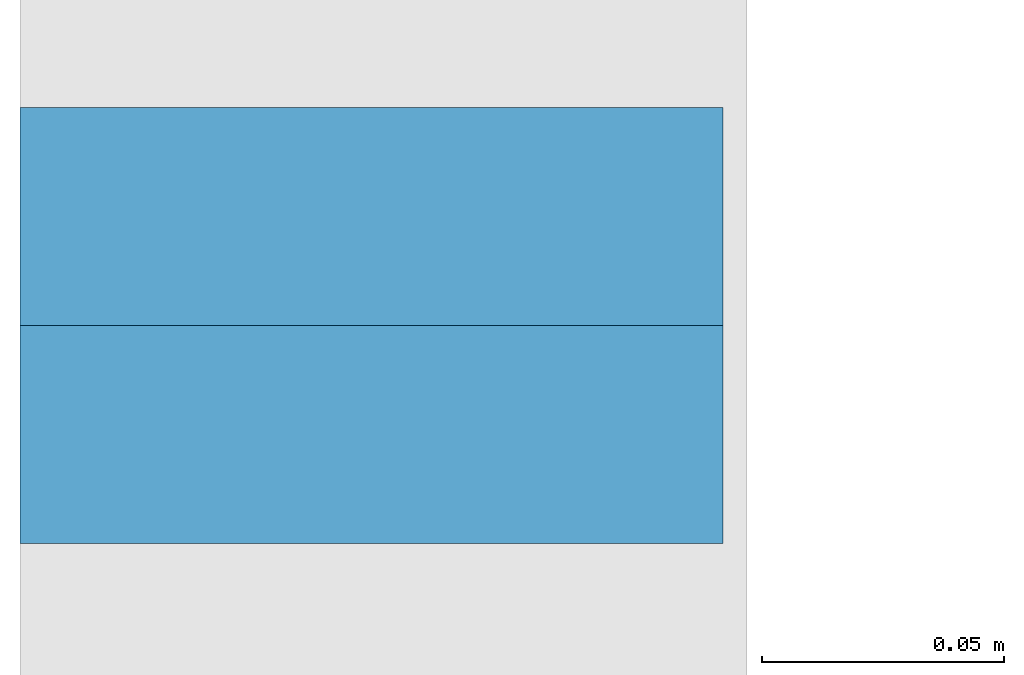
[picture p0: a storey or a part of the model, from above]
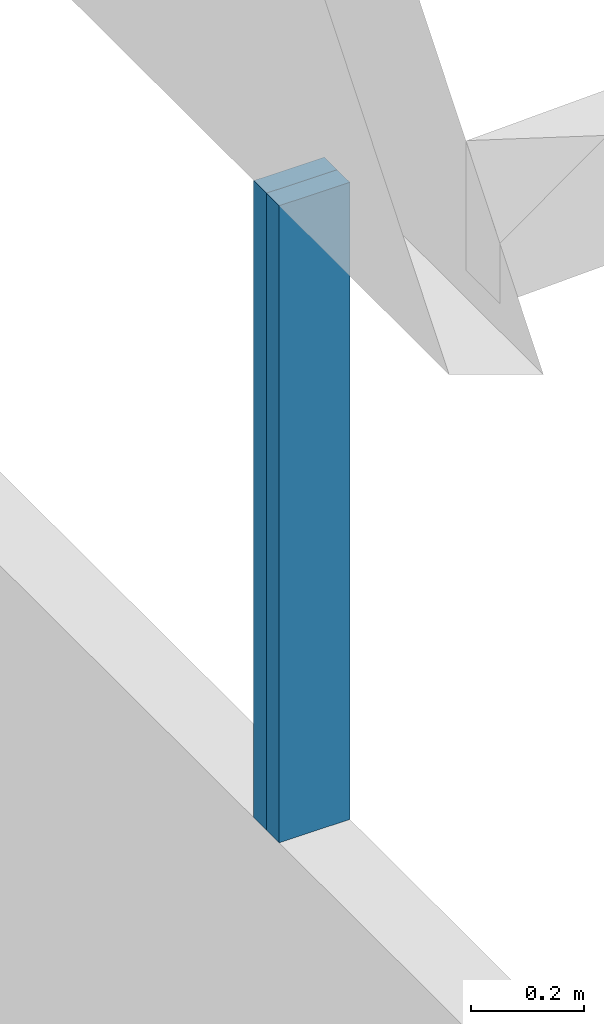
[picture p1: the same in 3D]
Properties of the parts of a building model (IFC2X3)

# File
Description: ViewDefinition[CoordinationView_V1.0], Option [GridExport:On], Option [Include assembly hierarchy:On], Option [Bolts:On], Option [Rebars:On], Option [PourObjects:Off], Option [Welds:Off], Option [SurfaceTreatments:On], Option [LocationBy:0], Option [ViewColors:On], Option [SectionedSpine:Off], Option [PropertySets:On], Option [Export all:Off], Option [Export selected and their assemblies:Off]
File name: IFC.ifc
Time: 2026-06-24T15:56:22
Author: INTECH\Bastien
Organization: Structural Designer
Written by: IFC Parser Version: 4.12.3
Made in: Trimble Inc. - Tekla Structures - 2026.0.60984.0

# IfcBuildingStorey, Undefined
In: Undefined
Elevation: 0 mm

# IfcBeam: 100*140 (2)
In: Undefined
Description: 100*140; Material: TIMBER/C24
Tekla Commun - Nom: BUTON; Profil: 100*140; Matériau: C24; Classe: 203; Phase: 1; Repère: Bu-b0(?); Repère assemblage: Bu-b0(?)
Tekla Quantités - Longueur: 1520 mm; Largeur: 140 mm; Hauteur: 100 mm; Surface nette: 0.758 m2; Surface par tonne: 84.765 m2; Surface: 0 m2; Volume: 0.021 m3; Poids: 8.94 kg
BeamBaseQuantities - Longueur: 1520 mm; Surface extérieure: 0.7 m2; Volume net: 0 m3; Poids net: 8.8 kg
Pset_BeamCommon - Inclinaison: 0 rad
Name | Niveau haut | Niveau bas
BUTON | +3.063 | +2.920
BUTON | +2.990 | +2.847

# IfcBeam: 120*280 (8)
In: Undefined
Description: 120*280; Material: TIMBER/C24
Tekla Commun - Profil: 120*280; Matériau: C24; Phase: 1
Tekla Quantités - Largeur: 280 mm; Hauteur: 120 mm; Surface: 0 m2
Name | Nom | Classe | Repère = Repère assemblage | Niveau haut | Niveau bas | Tekla Quantités, Longueur (mm) = BeamBaseQuantities, Longueur (mm) | Surface nette (m2) | Surface par tonne (m2) | Volume (m3) | Poids (kg) | Surface extérieure (m2) | Volume net (m3) | Poids net (kg) | Inclinaison (rad)
LIGNEUL | LIGNEUL | 207 | LL-b0(?) | +3.118 | +2.726 | 3834.5 | 3.135 | 57.931 | 0.129 | 54.11 | 3.1 | 0.1 | 54.1 | 0.02931
CHEVRONS | CHEVRONS | 201 | Cvr-b0(?) | +3.005 | +2.650 | 2171.1 | 1.796 | 58.894 | 0.073 | 30.5 | 1.8 | 0.1 | 30.5 | 0.03491
CHEVRONS | CHEVRONS | 201 | Cvr-b0(?) | +3.104 | +2.650 | 4996.8 | 4.011 | 58.072 | 0.164 | 69.07 | 4 | 0.2 | 69.1 | 0.03491
CHEVRONS | CHEVRONS | 201 | Cvr-b0(?) | +3.118 | +2.650 | 5386.4 | 4.368 | 57.576 | 0.181 | 75.87 | 4.4 | 0.2 | 75.9 | 0.03491
CHEVRONS | CHEVRONS | 201 | Cvr-b0(?) | +3.117 | +2.650 | 5381.3 | 4.364 | 57.576 | 0.18 | 75.8 | 4.4 | 0.2 | 75.8 | 0.03491
CHEVRONS | CHEVRONS | 201 | Cvr-b0(?) | +3.117 | +2.650 | 5376.2 | 4.36 | 57.576 | 0.18 | 75.73 | 4.4 | 0.2 | 75.8 | 0.03491
2 x CHEVRONS | CHEVRONS | 201 | Cvr-b0(?) | +3.120 | +2.650 | 5453.1 | 4.422 | 57.565 | 0.183 | 76.82 | 4.4 | 0.2 | 76.8 | 0.03491

# IfcBeam: 150*210 (5)
In: Undefined
Description: 150*210; Material: CONCRETE/C25/30
Tekla Commun - Nom: POUTRE; Profil: 150*210; Matériau: C25/30; Classe: 1; Phase: 1; Repère: Po0(?); Repère assemblage: Po0(?); Niveau haut: +0.210; Niveau bas: -0.000
Tekla Quantités - Largeur: 210 mm; Hauteur: 150 mm
Pset_BeamCommon - Inclinaison: 0 rad
Name | Tekla Quantités, Longueur (mm) = BeamBaseQuantities, Longueur (mm) | Surface nette (m2) | Surface par tonne (m2) | Surface (m2) | Volume (m3) | Poids (kg) | Surface extérieure (m2) | Volume net (m3) | Poids net (kg)
POUTRE | 435 | 0.376 | 11.44 | 0.065 | 0.014 | 32.89 | 0.4 | 0 | 32.9
POUTRE | 415 | 0.362 | 11.532 | 0.062 | 0.014 | 31.37 | 0.4 | 0 | 31.4
POUTRE | 5730 | 4.189 | 9.669 | 0.86 | 0.18 | 433.19 | 4.2 | 0.2 | 433.2
POUTRE | 10530 | 7.645 | 9.603 | 1.58 | 0.332 | 796.07 | 7.7 | 0.3 | 796.1
POUTRE | 2305 | 1.723 | 9.885 | 0.346 | 0.073 | 174.26 | 1.8 | 0.1 | 174.3

# IfcBeam: 170*1030, POUTRE
In: Undefined
Description: 170*1030; Material: CONCRETE/C25/30
Tekla Commun - Nom: POUTRE; Profil: 170*1030; Matériau: C25/30; Classe: 2; Phase: 1; Repère: Po0(?); Repère assemblage: Po0(?); Niveau haut: +3.630; Niveau bas: +2.600
Tekla Quantités - Longueur: 3490.7 mm; Largeur: 1030 mm; Hauteur: 170 mm; Surface nette: 8.728 m2; Surface par tonne: 5.95 m2; Surface: 0.593 m2; Volume: 0.611 m3; Poids: 1466.91 kg
BeamBaseQuantities - Longueur: 3490.7 mm; Surface extérieure: 8.7 m2; Volume net: 0.6 m3; Poids net: 1466.9 kg
Pset_BeamCommon - Inclinaison: 0 rad

# IfcBeam: 50*100 (12)
In: Undefined
Description: 50*100; Material: TIMBER/C24
Tekla Commun - Nom: CHEVETRE; Profil: 50*100; Matériau: C24; Classe: 204; Phase: 1; Repère: Ch-b0(?); Repère assemblage: Ch-b0(?)
Tekla Quantités - Largeur: 100 mm; Hauteur: 50 mm; Surface: 0 m2
BeamBaseQuantities - Volume net: 0 m3
Name | Niveau haut | Niveau bas | Tekla Quantités, Longueur (mm) = BeamBaseQuantities, Longueur (mm) | Surface nette (m2) | Surface par tonne (m2) | Volume (m3) | Poids (kg) | Surface extérieure (m2) | Poids net (kg) | Inclinaison (rad)
4 x CHEVETRE | +2.954 | +2.846 | 250 | 0.085 | 161.905 | 0.001 | 0.53 | 0.1 | 0.5 | 0.03491
CHEVETRE | +2.946 | +2.844 | 1520 | 0.466 | 145.99 | 0.008 | 3.19 | 0.4 | 3.2 | 0
CHEVETRE | +2.956 | +2.855 | 1520 | 0.466 | 145.99 | 0.008 | 3.19 | 0.4 | 3.2 | 0
CHEVETRE | +2.946 | +2.844 | 1580 | 0.484 | 145.871 | 0.008 | 3.32 | 0.4 | 3.3 | 0
CHEVETRE | +2.956 | +2.855 | 1580 | 0.484 | 145.871 | 0.008 | 3.32 | 0.4 | 3.3 | 0
CHEVETRE | +3.011 | +2.909 | 400 | 0.13 | 154.762 | 0.002 | 0.84 | 0.1 | 0.9 | 0
CHEVETRE | +2.995 | +2.894 | 400 | 0.13 | 154.762 | 0.002 | 0.84 | 0.1 | 0.9 | 0
2 x CHEVETRE | +3.060 | +2.890 | 2000 | 0.61 | 145.238 | 0.009 | 4.2 | 0.7 | 4.2 | 0.03491

# IfcBeam: 70*140 (17)
In: Undefined
Description: 70*140; Material: TIMBER/C24
Tekla Commun - Nom: BUTON; Profil: 70*140; Matériau: C24; Phase: 1; Repère: Bu-b0(?); Repère assemblage: Bu-b0(?)
Tekla Quantités - Largeur: 140 mm; Hauteur: 70 mm; Surface: 0 m2
BeamBaseQuantities - Volume net: 0 m3
Name | Classe | Niveau haut | Niveau bas | Tekla Quantités, Longueur (mm) = BeamBaseQuantities, Longueur (mm) | Surface nette (m2) | Surface par tonne (m2) | Volume (m3) | Poids (kg) | Surface extérieure (m2) | Poids net (kg) | Inclinaison (rad)
BUTON | 202 | +2.849 | +2.649 | 2370 | 1.015 | 104.05 | 0.023 | 9.75 | 0.9 | 9.8 | 0.02462
4 x BUTON | 202 | +2.849 | +2.649 | 2384.2 | 1.021 | 104.038 | 0.023 | 9.81 | 0.9 | 9.8 | 0.02447
BUTON | 202 | +2.849 | +2.649 | 2341.8 | 1.003 | 104.074 | 0.023 | 9.64 | 0.9 | 9.6 | 0.02492
BUTON | 202 | +2.923 | +2.708 | 2701.9 | 1.154 | 103.803 | 0.026 | 11.12 | 1.2 | 11.1 | 0.02713
BUTON | 202 | +2.978 | +2.781 | 2330.8 | 0.999 | 104.084 | 0.023 | 9.59 | 0.9 | 9.6 | 0.02388
4 x BUTON | 203 | +3.063 | +2.921 | 1580 | 0.683 | 105.055 | 0.014 | 6.5 | 0.7 | 6.5 | 0
BUTON | 203 | +2.990 | +2.847 | 1560 | 0.675 | 105.093 | 0.014 | 6.42 | 0.7 | 6.5 | 0
4 x BUTON | 203 | +2.990 | +2.847 | 1580 | 0.683 | 105.055 | 0.014 | 6.5 | 0.7 | 6.5 | 0

# IfcBeam: C40*30*2 (4)
In: Undefined
Description: C40*30*2; Material: STEEL/S235JR
Tekla Commun - Nom: OMEGA; Profil: C40*30*2; Matériau: S235JR; Classe: 503; Phase: 1; Repère: Om0(?); Repère assemblage: Om0(?); Niveau haut: +2.970; Niveau bas: +2.940
Tekla Quantités - Largeur: 30 mm; Hauteur: 40 mm
BeamBaseQuantities - Volume net: 0 m3
Pset_BeamCommon - Inclinaison: 0 rad
Name | Tekla Quantités, Longueur (mm) = BeamBaseQuantities, Longueur (mm) | Surface nette (m2) | Surface par tonne (m2) | Surface (m2) | Volume (m3) | Poids (kg) | Surface extérieure (m2) | Poids net (kg)
OMEGA | 1900 | 0.373 | 130.177 | 0.076 | 0 | 2.86 | 0.4 | 2.9
3 x OMEGA | 3480 | 0.682 | 130.116 | 0.139 | 0.001 | 5.25 | 0.7 | 5.2

# IfcBeam: D20 (4)
In: Undefined
Description: D20; Material: STEEL/S235JR
Tekla Commun - Nom: TIRANT; Profil: D20; Matériau: S235JR; Classe: 202; Phase: 1; Repère: Cv0(?); Repère assemblage: Cv0(?); Niveau haut: +3.100; Niveau bas: +2.897
Tekla Quantités - Longueur: 3507.4 mm; Largeur: 20 mm; Hauteur: 20 mm; Surface nette: 0.215 m2; Surface par tonne: 27.65 m2; Surface: 0 m2; Volume: 0.001 m3; Poids: 7.79 kg
BeamBaseQuantities - Longueur: 3507.4 mm; Surface extérieure: 0.2 m2; Volume net: 0 m3; Poids net: 7.8 kg
Pset_BeamCommon - Inclinaison: 0.05216 rad

# IfcBeam: TUBE-C-100*100*3 (10)
In: Undefined
Description: TUBE-C-100*100*3; Material: STEEL/S235JR
Tekla Commun - Nom: TUBE; Profil: TUBE-C-100*100*3; Matériau: S235JR; Classe: 203; Phase: 1; Repère: Tu0(?); Repère assemblage: Tu0(?)
Tekla Quantités - Largeur: 100 mm; Hauteur: 100 mm; Surface par tonne: 43.58 m2
BeamBaseQuantities - Surface extérieure: 0.4 m2; Volume net: 0 m3
Pset_BeamCommon - Inclinaison: 0 rad
Name | Niveau haut | Niveau bas | Tekla Quantités, Longueur (mm) = BeamBaseQuantities, Longueur (mm) | Surface nette (m2) | Surface (m2) | Volume (m3) | Poids (kg) | Poids net (kg)
2 x TUBE | +0.250 | +0.150 | 1320 | 0.529 | 0.132 | 0.002 | 11.81 | 12.1
2 x TUBE | +1.720 | +1.620 | 1320 | 0.529 | 0.132 | 0.002 | 11.81 | 12.1
3 x TUBE | +0.250 | +0.150 | 920 | 0.369 | 0.092 | 0.001 | 8.23 | 8.4
3 x TUBE | +1.720 | +1.620 | 920 | 0.369 | 0.092 | 0.001 | 8.23 | 8.4

# IfcBeam: TUBE-C-80*80*3 (87)
In: Undefined
Description: TUBE-C-80*80*3; Material: STEEL/S235JR
Tekla Commun - Profil: TUBE-C-80*80*3; Matériau: S235JR; Phase: 1
Tekla Quantités - Largeur: 80 mm; Hauteur: 80 mm; Surface par tonne: 43.688 m2
BeamBaseQuantities - Volume net: 0 m3
Name | Nom | Classe | Repère = Repère assemblage | Niveau haut | Niveau bas | Tekla Quantités, Longueur (mm) = BeamBaseQuantities, Longueur (mm) | Surface nette (m2) | Surface (m2) | Volume (m3) | Poids (kg) | Surface extérieure (m2) | Poids net (kg) | Inclinaison (rad)
LISSE | LISSE | 207 | L0(?) | +3.630 | +3.550 | 1595.6 | 0.512 | 0.128 | 0.001 | 11.29 | 0.4 | 11.6 | 0
LISSE | LISSE | 207 | L0(?) | +3.050 | +2.970 | 1595.6 | 0.512 | 0.128 | 0.001 | 11.29 | 0.4 | 11.6 | 0
TREILLIS | TREILLIS | 200 | Tr0(?) | +3.010 | +2.880 | 129.8 | 0.043 | 0.001 | 0 | 0.92 | 0 | 0.9 | 1.5708
2 x TREILLIS | TREILLIS | 200 | Tr0(?) | +2.400 | +2.320 | 1115 | 0.358 | 0.089 | 0.001 | 7.89 | 0.4 | 8.1 | 0
TREILLIS | TREILLIS | 200 | Tr0(?) | +2.880 | +2.800 | 1750 | 0.561 | 0.14 | 0.002 | 12.38 | 0.4 | 12.7 | 0
LISSE | LISSE | 207 | L0(?) | +3.050 | +2.970 | 1900 | 0.609 | 0.152 | 0.002 | 13.44 | 0.7 | 13.8 | 0
LISSE | LISSE | 207 | L0(?) | +3.630 | +3.550 | 1900 | 0.609 | 0.152 | 0.002 | 13.44 | 0.7 | 13.8 | 0
2 x PANNE | PANNE | 201 | Pa0(?) | +3.043 | +2.957 | 3040 | 0.974 | 0 | 0.003 | 21.5 | 0.9 | 22.1 | 0
LISSE | LISSE | 207 | L0(?) | +3.630 | +3.550 | 1560 | 0.5 | 0.125 | 0.001 | 11.03 | 0.4 | 11.3 | 0
LISSE | LISSE | 207 | L0(?) | +3.630 | +3.550 | 2360 | 0.756 | 0.189 | 0.002 | 16.69 | 0.7 | 17.1 | 0
LISSE | LISSE | 207 | L0(?) | +3.630 | +3.550 | 800 | 0.257 | 0.064 | 0.001 | 5.66 | 0.2 | 5.8 | 0
LISSE | LISSE | 207 | L0(?) | +3.050 | +2.970 | 1560 | 0.5 | 0.125 | 0.001 | 11.03 | 0.4 | 11.3 | 0
LISSE | LISSE | 207 | L0(?) | +3.050 | +2.970 | 2360 | 0.756 | 0.189 | 0.002 | 16.69 | 0.7 | 17.1 | 0
2 x PANNE | PANNE | 201 | Pa0(?) | +3.704 | +3.624 | 3170 | 1.015 | 0.254 | 0.003 | 22.42 | 0.9 | 23 | 0
2 x PANNE | PANNE | 201 | Pa0(?) | +3.704 | +3.624 | 2680 | 0.859 | 0.214 | 0.002 | 18.96 | 0.7 | 19.4 | 0
LISSE | LISSE | 207 | L0(?) | +2.400 | +2.320 | 2870 | 0.919 | 0.23 | 0.003 | 20.3 | 0.9 | 20.8 | 0
LISSE | LISSE | 207 | L0(?) | +2.400 | +2.320 | 2740 | 0.878 | 0.219 | 0.002 | 19.38 | 0.7 | 19.9 | 0
2 x PANNE | PANNE | 201 | Pa0(?) | +2.947 | +2.867 | 3040 | 0.974 | 0.243 | 0.003 | 21.5 | 0.9 | 22.1 | 0
PANNE | PANNE | 201 | Pa0(?) | +3.130 | +3.050 | 3040 | 0.974 | 0.243 | 0.003 | 21.5 | 0.9 | 22.1 | 0
2 x TREILLIS | TREILLIS | 200 | Tr0(?) | +2.868 | +2.323 | 1219.8 | 0.391 | 0 | 0.001 | 8.63 | 0.4 | 8.8 | 0.39677
2 x TREILLIS | TREILLIS | 200 | Tr0(?) | +2.930 | +2.400 | 529.8 | 0.17 | 0.001 | 0 | 3.75 | 0.2 | 3.8 | 1.5708
4 x TREILLIS | TREILLIS | 200 | Tr0(?) | +3.050 | +2.787 | 2098 | 0.672 | 0 | 0.002 | 14.84 | 0.7 | 15.2 | 0.08727
2 x TREILLIS | TREILLIS | 200 | Tr0(?) | +2.956 | +2.325 | 1159.7 | 0.372 | 0 | 0.001 | 8.2 | 0.4 | 8.4 | 0.50496
2 x TREILLIS | TREILLIS | 200 | Tr0(?) | +2.868 | +2.324 | 1128.2 | 0.362 | 0 | 0.001 | 7.98 | 0.4 | 8.2 | 0.43103
2 x TREILLIS | TREILLIS | 200 | Tr0(?) | +2.921 | +2.400 | 521 | 0.168 | 0.001 | 0 | 3.69 | 0.2 | 3.8 | 1.5708
TREILLIS | TREILLIS | 200 | Tr0(?) | +3.010 | +2.400 | 609.8 | 0.196 | 0.001 | 0.001 | 4.31 | 0.2 | 4.4 | 1.5708
TREILLIS | TREILLIS | 200 | Tr0(?) | +2.400 | +2.320 | 3980 | 1.275 | 0.318 | 0.004 | 28.15 | 1.2 | 28.9 | 0
LISSE | LISSE | 207 | L0(?) | +3.050 | +2.970 | 800 | 0.257 | 0.064 | 0.001 | 5.66 | 0.2 | 5.8 | 0
2 x LISSE | LISSE | 207 | L0(?) | +3.050 | +2.970 | 3110 | 0.996 | 0.249 | 0.003 | 22 | 0.9 | 22.6 | 0
2 x LISSE | LISSE | 207 | L0(?) | +3.050 | +2.970 | 2600 | 0.832 | 0.208 | 0.002 | 18.39 | 0.7 | 18.9 | 0
2 x PANNE | PANNE | 201 | Pa0(?) | +3.630 | +3.550 | 3170 | 1.015 | 0.254 | 0.003 | 22.42 | 0.9 | 23 | 0
2 x PANNE | PANNE | 201 | Pa0(?) | +3.630 | +3.550 | 2680 | 0.859 | 0.214 | 0.002 | 18.96 | 0.7 | 19.4 | 0
PANNE | PANNE | 201 | Pa0(?) | +3.778 | +3.698 | 3170 | 1.015 | 0.254 | 0.003 | 22.42 | 0.9 | 23 | 0
PANNE | PANNE | 201 | Pa0(?) | +3.778 | +3.698 | 2680 | 0.859 | 0.214 | 0.002 | 18.96 | 0.7 | 19.4 | 0
3 x TREILLIS | TREILLIS | 200 | Tr0(?) | +3.050 | +2.970 | 3480 | 1.115 | 0.278 | 0.003 | 24.61 | 1.1 | 25.2 | 0
6 x TREILLIS | TREILLIS | 200 | Tr0(?) | +3.544 | +2.976 | 985.8 | 0.316 | 0 | 0.001 | 6.97 | 0.4 | 7.2 | 0.5311
6 x TREILLIS | TREILLIS | 200 | Tr0(?) | +3.617 | +2.977 | 1025.5 | 0.329 | 0 | 0.001 | 7.25 | 0.4 | 7.4 | 0.59367
TREILLIS | TREILLIS | 200 | Tr0(?) | +3.547 | +3.050 | 496.8 | 0.16 | 0.001 | 0 | 3.51 | 0.2 | 3.6 | 1.5708
2 x TREILLIS | TREILLIS | 200 | Tr0(?) | +3.546 | +3.050 | 495.9 | 0.16 | 0.001 | 0 | 3.51 | 0.2 | 3.6 | 1.5708
TREILLIS | TREILLIS | 200 | Tr0(?) | +3.548 | +3.050 | 497.7 | 0.16 | 0.001 | 0 | 3.51 | 0.2 | 3.6 | 1.5708
6 x TREILLIS | TREILLIS | 200 | Tr0(?) | +3.584 | +3.050 | 533.6 | 0.172 | 0.001 | 0 | 3.77 | 0.2 | 3.9 | 1.5708
TREILLIS | TREILLIS | 200 | Tr0(?) | +3.545 | +3.050 | 495.1 | 0.159 | 0.001 | 0 | 3.5 | 0.2 | 3.6 | 1.5708
3 x TREILLIS | TREILLIS | 200 | Tr0(?) | +3.658 | +3.050 | 608 | 0.196 | 0.001 | 0.001 | 4.3 | 0.2 | 4.4 | 1.5708
TREILLIS | TREILLIS | 200 | Tr0(?) | +3.698 | +3.467 | 1736.6 | 0.557 | 0 | 0.002 | 12.28 | 0.4 | 12.7 | 0.08727
TREILLIS | TREILLIS | 200 | Tr0(?) | +3.698 | +3.465 | 1756.7 | 0.563 | 0 | 0.002 | 12.42 | 0.4 | 12.7 | 0.08727
2 x TREILLIS | TREILLIS | 200 | Tr0(?) | +3.698 | +3.466 | 1746.6 | 0.56 | 0 | 0.002 | 12.35 | 0.4 | 12.7 | 0.08727
TREILLIS | TREILLIS | 200 | Tr0(?) | +3.544 | +3.050 | 494.2 | 0.159 | 0.001 | 0 | 3.5 | 0.2 | 3.6 | 1.5708
TREILLIS | TREILLIS | 200 | Tr0(?) | +3.698 | +3.468 | 1726.6 | 0.553 | 0 | 0.002 | 12.21 | 0.4 | 12.5 | 0.08727
TREILLIS | TREILLIS | 200 | Tr0(?) | +3.698 | +3.464 | 1766.7 | 0.566 | 0 | 0.002 | 12.5 | 0.4 | 12.7 | 0.08727

# IfcBeam: TUBE-R-140*80*3 (3)
In: Undefined
Description: TUBE-R-140*80*3; Material: STEEL/S235JR
Tekla Commun - Nom: TREILLIS; Profil: TUBE-R-140*80*3; Matériau: S235JR; Classe: 203; Phase: 1; Repère: Tr0(?); Repère assemblage: Tr0(?)
Tekla Quantités - Largeur: 80 mm; Hauteur: 140 mm; Surface par tonne: 42.695 m2
BeamBaseQuantities - Volume net: 0 m3
Pset_BeamCommon - Inclinaison: 0 rad
Name | Niveau haut | Niveau bas | Tekla Quantités, Longueur (mm) = BeamBaseQuantities, Longueur (mm) | Surface nette (m2) | Surface (m2) | Volume (m3) | Poids (kg) | Surface extérieure (m2) | Poids net (kg)
TREILLIS | +3.960 | +3.820 | 3480 | 1.523 | 0.278 | 0.004 | 34.97 | 1.5 | 35.1
TREILLIS | +4.095 | +3.955 | 1900 | 0.832 | 0.152 | 0.002 | 19.09 | 0.7 | 19.2
TREILLIS | +3.890 | +3.750 | 3480 | 1.523 | 0.278 | 0.004 | 34.97 | 1.5 | 35.1

# IfcColumn: 45*145 (2)
In: Undefined
Description: 45*145; Material: TIMBER/C24
Tekla Commun - Nom: POTEAU; Profil: 45*145; Matériau: C24; Classe: 42; Phase: 1; Repère: P-b0(?); Repère assemblage: P-b0(?); Niveau haut: +2.590; Niveau bas: +1.210
Tekla Quantités - Longueur: 1380 mm; Largeur: 145 mm; Hauteur: 45 mm; Surface nette: 0.537 m2; Surface par tonne: 142.111 m2; Surface: 0.007 m2; Volume: 0.009 m3; Poids: 3.78 kg
ColumnBaseQuantities - Longueur: 1380 mm; Surface extérieure: 0.4 m2; Volume net: 0 m3; Poids net: 3.8 kg
Pset_ColumnCommon - Inclinaison: 1.5708 rad

# IfcColumn: TUBE-C-100*100*3 (8)
In: Undefined
Description: TUBE-C-100*100*3; Material: STEEL/S235JR
Tekla Commun - Nom: POTEAU; Profil: TUBE-C-100*100*3; Matériau: S235JR; Phase: 1; Repère: P0(?); Repère assemblage: P0(?); Niveau bas: +0.000
Tekla Quantités - Largeur: 100 mm; Hauteur: 100 mm; Surface par tonne: 43.58 m2; Surface: 0.001 m2
ColumnBaseQuantities - Volume net: 0 m3
Pset_ColumnCommon - Inclinaison: 1.5708 rad
Name | Classe | Niveau haut | Tekla Quantités, Longueur (mm) = ColumnBaseQuantities, Longueur (mm) | Surface nette (m2) | Volume (m3) | Poids (kg) | Surface extérieure (m2) | Poids net (kg)
4 x POTEAU | 200 | +2.870 | 2870 | 1.149 | 0.003 | 25.68 | 1.1 | 26.2
4 x POTEAU | 203 | +1.720 | 1720 | 0.689 | 0.002 | 15.39 | 0.7 | 15.7

# IfcColumn: TUBE-C-80*80*3 (4)
In: Undefined
Description: TUBE-C-80*80*3; Material: STEEL/S235JR
Tekla Commun - Nom: MONTANT; Profil: TUBE-C-80*80*3; Matériau: S235JR; Classe: 207; Phase: 1; Repère: Mt0(?); Repère assemblage: Mt0(?); Niveau haut: +2.870; Niveau bas: +2.400
Tekla Quantités - Longueur: 470 mm; Largeur: 80 mm; Hauteur: 80 mm; Surface nette: 0.151 m2; Surface par tonne: 43.688 m2; Surface: 0.001 m2; Volume: 0 m3; Poids: 3.32 kg
ColumnBaseQuantities - Longueur: 470 mm; Surface extérieure: 0.1 m2; Volume net: 0 m3; Poids net: 3.4 kg
Pset_ColumnCommon - Inclinaison: 1.5708 rad

# IfcElementAssembly (186)
In: Undefined
Name | Repère Assemblage/Elément béton | Position maillage Assemblage/Elément béton | Niveau Haut Assemblage/Elément béton | Niveau Bas Assemblage/Elément béton | Poids Assemblage/Elément béton (kg) | Largeur (mm)
OMEGA | Om0(?) | -/5 | +2.970 | +2.940 | 2.9 | 30
OMEGA | Om0(?) | -/4 | +2.970 | +2.940 | 5.2 | 30
OMEGA | Om0(?) | -/2 | +2.970 | +2.940 | 5.2 | 30
OMEGA | Om0(?) | -/1 | +2.970 | +2.940 | 5.2 | 30
LISSE | L0(?) |  | +3.630 | +3.550 | 11.3 | 80
LISSE | L0(?) |  | +3.050 | +2.970 | 11.3 | 80
2 x POTEAU | P-b0(?) | 1/A-B | +2.590 | +1.210 | 3.8 | 145
TREILLIS | Tr0(?) | 1/A-B | +3.010 | +2.880 | 0.9 | 80
2 x TREILLIS | Tr0(?) | 1/A-B | +2.400 | +2.320 | 7.9 | 80
TREILLIS | Tr0(?) | 1/A-B | +2.880 | +2.800 | 12.4 | 80
LISSE | L0(?) | -/5 | +3.050 | +2.970 | 13.4 | 80
LISSE | L0(?) | -/5 | +3.630 | +3.550 | 13.4 | 80
PANNEAU | PA0(?) | /<4 | +3.630 | +0.000 | 10549.4 | 200 | Tekla Assemblages - Poids ferraillage Elément béton: 0 kg; Type Elément béton: Coulé sur site
PANNEAU | PA0(?) | /<5-5> | +5.000 | +0.000 | 7835.5 | 200 | Tekla Assemblages - Poids ferraillage Elément béton: 0 kg; Type Elément béton: Coulé sur site
PANNEAU | PA0(?) | >/4 | +5.000 | +0.000 | 7755.1 | 200 | Tekla Assemblages - Poids ferraillage Elément béton: 0 kg; Type Elément béton: Coulé sur site
PANNEAU | PA0(?) | </4 | +5.000 | +0.000 | 7105 | 200 | Tekla Assemblages - Poids ferraillage Elément béton: 0 kg; Type Elément béton: Coulé sur site
2 x MONTANT | Mt0(?) | 1-2/B | +2.870 | +2.400 | 3.3 | 80
2 x MONTANT | Mt0(?) | 1-2/A | +2.870 | +2.400 | 3.3 | 80
POTEAU | P0(?) | 1/B | +2.870 | +0.000 | 25.7 | 100
2 x PANNE | Pa0(?) | 1-2/A-B | +3.043 | +2.957 | 21.5 | 80
LISSE | L0(?) | -/<5 | +3.630 | +3.550 | 11 | 80
LISSE | L0(?) | /<5 | +3.630 | +3.550 | 16.7 | 80
LISSE | L0(?) | /4> | +3.630 | +3.550 | 5.7 | 80
LISSE | L0(?) | -/<5 | +3.050 | +2.970 | 11 | 80
LISSE | L0(?) | /<5 | +3.050 | +2.970 | 16.7 | 80
TREILLIS | Tr0(?) |  | +3.960 | +3.820 | 35 | 80
2 x PANNE | Pa0(?) | -/<4 | +3.704 | +3.624 | 22.4 | 80
2 x PANNE | Pa0(?) | -/<2 | +3.704 | +3.624 | 19 | 80
4 x CHEVETRE | Ch-b0(?) | 1-2/A-B | +2.954 | +2.846 | 0.5 | 100
CHEVETRE | Ch-b0(?) | 1-2/A-B | +2.946 | +2.844 | 3.2 | 100
CHEVETRE | Ch-b0(?) | 1-2/A-B | +2.956 | +2.855 | 3.2 | 100
CHEVETRE | Ch-b0(?) | 1-2/A-B | +2.946 | +2.844 | 3.3 | 100
CHEVETRE | Ch-b0(?) | 1-2/A-B | +2.956 | +2.855 | 3.3 | 100
CHEVETRE | Ch-b0(?) | 1-2/A-B | +3.011 | +2.909 | 0.9 | 100
CHEVETRE | Ch-b0(?) | 1-2/A-B | +2.995 | +2.894 | 0.9 | 100
PANNEAU | PA0(?) | 2/A-B | +3.670 | -0.000 | 138641 | 33127.8 | Tekla Assemblages - Poids ferraillage Elément béton: 0 kg; Type Elément béton: Coulé sur site
PANNEAU | PA0(?) |  | +3.670 | +0.000 | 9009 | 200 | Tekla Assemblages - Poids ferraillage Elément béton: 0 kg; Type Elément béton: Coulé sur site
PANNEAU | PA0(?) | >/1 | +3.760 | +0.000 | 33070.8 | 6551.4 | Tekla Assemblages - Poids ferraillage Elément béton: 0 kg; Type Elément béton: Coulé sur site
2 x TUBE | Tu0(?) | 1-2/A | +0.250 | +0.150 | 11.8 | 100
2 x TUBE | Tu0(?) | 1-2/A | +1.720 | +1.620 | 11.8 | 100
TUBE | Tu0(?) | 2/A-B | +0.250 | +0.150 | 8.2 | 100
TUBE | Tu0(?) | 1-2/A-B | +0.250 | +0.150 | 8.2 | 100
TUBE | Tu0(?) | 1/A-B | +0.250 | +0.150 | 8.2 | 100
TUBE | Tu0(?) | 2/A-B | +1.720 | +1.620 | 8.2 | 100
TUBE | Tu0(?) | 1-2/A-B | +1.720 | +1.620 | 8.2 | 100
TUBE | Tu0(?) | 1/A-B | +1.720 | +1.620 | 8.2 | 100
POTEAU | P0(?) | 2/A-B | +1.720 | +0.000 | 15.4 | 100
POTEAU | P0(?) | 1/A-B | +1.720 | +0.000 | 15.4 | 100
POTEAU | P0(?) | 1-2/A-B | +1.720 | +0.000 | 15.4 | 100
POTEAU | P0(?) | 1/A | +2.870 | +0.000 | 25.7 | 100
POTEAU | P0(?) | 1-2/A | +1.720 | +0.000 | 15.4 | 100
4 x TIRANT | Cv0(?) | 1-2/A-B | +3.100 | +2.897 | 7.9 | 20
LISSE | L0(?) | 1-2/B | +2.400 | +2.320 | 20.3 | 80
LISSE | L0(?) | 1-2/A | +2.400 | +2.320 | 19.4 | 80
PANNE | Pa0(?) | 1-2/B | +2.947 | +2.867 | 21.5 | 80
PANNE | Pa0(?) | 1-2/A | +2.947 | +2.867 | 21.5 | 80
PANNE | Pa0(?) | 1-2/A-B | +3.130 | +3.050 | 21.5 | 80
2 x TREILLIS | Tr0(?) | 1/A-B | +2.868 | +2.323 | 8.6 | 80
2 x TREILLIS | Tr0(?) | 1/A-B | +2.930 | +2.400 | 3.7 | 80
2 x TREILLIS | Tr0(?) | 1/A-B | +3.050 | +2.787 | 14.8 | 80
2 x TREILLIS | Tr0(?) | 2/A-B | +2.956 | +2.325 | 8.2 | 80
2 x TREILLIS | Tr0(?) | 2/A-B | +2.868 | +2.324 | 7.9 | 80
2 x TREILLIS | Tr0(?) | 2/A-B | +2.921 | +2.400 | 3.7 | 80
TREILLIS | Tr0(?) | 2/A-B | +3.010 | +2.400 | 4.3 | 80
TREILLIS | Tr0(?) | 2/A-B | +2.400 | +2.320 | 28.1 | 80
2 x TREILLIS | Tr0(?) | 2/A-B | +3.050 | +2.787 | 14.8 | 80
POTEAU | P0(?) | 2/B | +2.870 | +0.000 | 25.7 | 100
POTEAU | P0(?) | 2/A | +2.870 | +0.000 | 25.7 | 100
POUTRE | Po0(?) | 2/A-B | +0.210 | -0.000 | 32.9 | 210 | Tekla Assemblages - Poids ferraillage Elément béton: 0 kg; Type Elément béton: Préfabriqué
2 x CHEVETRE | Ch-b0(?) | 1-2/A-B | +3.060 | +2.890 | 4.3 | 100
5 x BUTON | Bu-b0(?) | 1-2/A-B | +2.849 | +2.649 | 9.8 | 140
BUTON | Bu-b0(?) | 1-2/A-B | +2.849 | +2.649 | 9.6 | 140
BUTON | Bu-b0(?) | 1-2/A-B | +2.923 | +2.708 | 11.1 | 140
BUTON | Bu-b0(?) | 1-2/A-B | +2.978 | +2.781 | 9.6 | 140
4 x BUTON | Bu-b0(?) | 1-2/A-B | +3.063 | +2.921 | 6.5 | 140
BUTON | Bu-b0(?) | 1-2/A-B | +3.063 | +2.920 | 8.9 | 140
5 x BUTON | Bu-b0(?) | 1-2/A-B | +2.990 | +2.847 | 6.5 | 140
BUTON | Bu-b0(?) | 1-2/A-B | +2.990 | +2.847 | 8.9 | 140
LIGNEUL | LL-b0(?) | 1-2/A-B | +3.118 | +2.726 | 54.1 | 280
CHEVRONS | Cvr-b0(?) | 1-2/B | +3.005 | +2.650 | 30.5 | 280
CHEVRONS | Cvr-b0(?) | 1-2/A-B | +3.104 | +2.650 | 69.1 | 280
CHEVRONS | Cvr-b0(?) | 1-2/A-B | +3.118 | +2.650 | 75.9 | 280
2 x CHEVRONS | Cvr-b0(?) | 1-2/A-B | +3.117 | +2.650 | 75.8 | 280
CHEVRONS | Cvr-b0(?) | 1-2/A-B | +3.120 | +2.650 | 76.8 | 280
CHEVRONS | Cvr-b0(?) | 1-2/A | +3.120 | +2.650 | 76.8 | 280
MOB 145x45 | PA0(?) | 2/A-B | +3.630 | +0.210 | 272 | 145
MOB 145x45 | PA0(?) | 1-2/A | +3.630 | +0.210 | 1040.1 | 145
MOB 145x45 | PA0(?) | 1/A-B | +3.630 | +0.210 | 1728.4 | 145
MOB 145x45 | PA0(?) | 1-2/B | +3.630 | +0.210 | 480.1 | 145
PANNEAU | PA0(?) |  | +3.760 | -0.000 | 6368.2 | 200 | Tekla Assemblages - Poids ferraillage Elément béton: 0 kg; Type Elément béton: Coulé sur site
POUTRE | Po0(?) | 2/A | +0.210 | -0.000 | 31.4 | 210 | Tekla Assemblages - Poids ferraillage Elément béton: 0 kg; Type Elément béton: Préfabriqué
POUTRE | Po0(?) | 1-2/A | +0.210 | -0.000 | 433.2 | 210 | Tekla Assemblages - Poids ferraillage Elément béton: 0 kg; Type Elément béton: Préfabriqué
POUTRE | Po0(?) | 1/A-B | +0.210 | -0.000 | 796.1 | 210 | Tekla Assemblages - Poids ferraillage Elément béton: 0 kg; Type Elément béton: Préfabriqué
POUTRE | Po0(?) | 1-2/B | +0.210 | -0.000 | 174.3 | 210 | Tekla Assemblages - Poids ferraillage Elément béton: 0 kg; Type Elément béton: Préfabriqué
LISSE | L0(?) | /4> | +3.050 | +2.970 | 5.7 | 80
TREILLIS | Tr0(?) | -/5 | +4.095 | +3.955 | 19.1 | 80
2 x LISSE | L0(?) | /<3 | +3.050 | +2.970 | 22 | 80
2 x LISSE | L0(?) | /<2 | +3.050 | +2.970 | 18.4 | 80
PANNEAU | PA0(?) | -/5 | +5.000 | +2.180 | 3555.6 | 150 | Tekla Assemblages - Poids ferraillage Elément béton: 0 kg; Type Elément béton: Coulé sur site
TREILLIS | Tr0(?) | -/4 | +3.890 | +3.750 | 35 | 80
2 x PANNE | Pa0(?) | /<4 | +3.630 | +3.550 | 22.4 | 80
2 x PANNE | Pa0(?) | /<2 | +3.630 | +3.550 | 19 | 80
PANNE | Pa0(?) | -/<4 | +3.778 | +3.698 | 22.4 | 80
PANNE | Pa0(?) | -/<2 | +3.778 | +3.698 | 19 | 80
PANNEAU | PA0(?) |  | +5.000 | +0.000 | 3850.6 | 200 | Tekla Assemblages - Poids ferraillage Elément béton: 0 kg; Type Elément béton: Coulé sur site
PANNEAU | PA0(?) | -/<5 | +5.000 | +0.000 | 4113 | 200 | Tekla Assemblages - Poids ferraillage Elément béton: 0 kg; Type Elément béton: Coulé sur site
TREILLIS | Tr0(?) | -/4 | +3.050 | +2.970 | 24.6 | 80
TREILLIS | Tr0(?) | -/2 | +3.050 | +2.970 | 24.6 | 80
TREILLIS | Tr0(?) | -/1 | +3.050 | +2.970 | 24.6 | 80
2 x TREILLIS | Tr0(?) | -/4 | +3.544 | +2.976 | 7 | 80
2 x TREILLIS | Tr0(?) | -/4 | +3.617 | +2.977 | 7.3 | 80
2 x TREILLIS | Tr0(?) | -/2 | +3.544 | +2.976 | 7 | 80
2 x TREILLIS | Tr0(?) | -/2 | +3.617 | +2.977 | 7.3 | 80
2 x TREILLIS | Tr0(?) | -/1 | +3.544 | +2.976 | 7 | 80
2 x TREILLIS | Tr0(?) | -/1 | +3.617 | +2.977 | 7.3 | 80
TREILLIS | Tr0(?) | /2 | +3.547 | +3.050 | 3.5 | 80
2 x TREILLIS | Tr0(?) | /4 | +3.546 | +3.050 | 3.5 | 80
TREILLIS | Tr0(?) | /1 | +3.548 | +3.050 | 3.5 | 80
2 x TREILLIS | Tr0(?) | -/2 | +3.584 | +3.050 | 3.8 | 80
TREILLIS | Tr0(?) | /2 | +3.545 | +3.050 | 3.5 | 80
TREILLIS | Tr0(?) | -/2 | +3.658 | +3.050 | 4.3 | 80
TREILLIS | Tr0(?) | -/2 | +3.698 | +3.467 | 12.4 | 80
TREILLIS | Tr0(?) | -/2 | +3.698 | +3.465 | 12.4 | 80
2 x TREILLIS | Tr0(?) | -/4 | +3.584 | +3.050 | 3.8 | 80
TREILLIS | Tr0(?) | -/4 | +3.658 | +3.050 | 4.3 | 80
2 x TREILLIS | Tr0(?) | -/4 | +3.698 | +3.466 | 12.4 | 80
2 x TREILLIS | Tr0(?) | -/1 | +3.584 | +3.050 | 3.8 | 80
TREILLIS | Tr0(?) | /1 | +3.544 | +3.050 | 3.5 | 80
TREILLIS | Tr0(?) | -/1 | +3.658 | +3.050 | 4.3 | 80
TREILLIS | Tr0(?) | -/1 | +3.698 | +3.468 | 12.2 | 80
TREILLIS | Tr0(?) | -/1 | +3.698 | +3.464 | 12.4 | 80
POUTRE | Po0(?) | -/1 | +3.630 | +2.600 | 1466.9 | 1030 | Tekla Assemblages - Poids ferraillage Elément béton: 0 kg; Type Elément béton: Préfabriqué
PANNEAU | PA0(?) |  | +5.000 | +0.000 | 8405.8 | 200 | Tekla Assemblages - Poids ferraillage Elément béton: 0 kg; Type Elément béton: Coulé sur site
PANNEAU | PA0(?) | /<5-5> | +5.000 | +0.000 | 7938.8 | 200 | Tekla Assemblages - Poids ferraillage Elément béton: 0 kg; Type Elément béton: Coulé sur site
PANNEAU | PA0(?) | /<4 | +3.630 | +0.000 | 16845.5 | 200 | Tekla Assemblages - Poids ferraillage Elément béton: 0 kg; Type Elément béton: Coulé sur site
PANNEAU | PA0(?) |  | +3.760 | +0.000 | 10775.3 | 200 | Tekla Assemblages - Poids ferraillage Elément béton: 0 kg; Type Elément béton: Coulé sur site

# IfcWall: 3420*145 (3)
In: Undefined
Description: 3420*145; Material: TIMBER/C24
Tekla Commun - Nom: MOB 145x45; Profil: 3420*145; Matériau: C24; Classe: 42; Phase: 1; Repère: PA0(?); Repère assemblage: PA0(?); Niveau haut: +3.630; Niveau bas: +0.210
Tekla Quantités - Largeur: 145 mm; Hauteur: 3420 mm
Name | Tekla Quantités, Longueur (mm) = WallBaseQuantities, Longueur (mm) | Surface nette (m2) | Surface par tonne (m2) | Surface (m2) | Volume (m3) | Poids (kg) | Surface extérieure (m2) | Volume net (m3) | Poids net (kg)
MOB 145x45 | 1940 | 11.063 | 40.678 | 0.281 | 0.648 | 271.96 | 11.1 | 0.6 | 272
MOB 145x45 | 5730 | 37.739 | 36.286 | 0.831 | 2.476 | 1040.06 | 37.7 | 2.5 | 1040.1
MOB 145x45 | 10530 | 63.212 | 36.572 | 1.527 | 4.115 | 1728.42 | 63.2 | 4.1 | 1728.4

# IfcWall: 3670*200 (24)
In: Undefined
Description: 3670*200; Material: CONCRETE/C25/30
Tekla Commun - Nom: PANNEAU; Profil: 3670*200; Matériau: C25/30; Classe: 2; Phase: 1; Repère: Béton_PA-10(?); Repère assemblage: PA0(?); Niveau haut: +3.670
Tekla Quantités - Largeur: 200 mm; Hauteur: 3670 mm
Name | Niveau bas | Tekla Quantités, Longueur (mm) = WallBaseQuantities, Longueur (mm) | Surface nette (m2) | Surface par tonne (m2) | Surface (m2) | Volume (m3) | Poids (kg) | Surface extérieure (m2) | Volume net (m3) | Poids net (kg)
PANNEAU | +0.000 | 3872.3 | 30.709 | 4.663 | 0.748 | 2.744 | 6585.57 | 30.7 | 2.7 | 6585.6
PANNEAU | +0.000 | 4463.7 | 35.382 | 4.611 | 0.871 | 3.197 | 7673.23 | 35.4 | 3.2 | 7673.2
PANNEAU | +0.000 | 3853.9 | 30.567 | 4.663 | 0.744 | 2.731 | 6553.51 | 30.6 | 2.7 | 6553.5
PANNEAU | +0.000 | 3878.3 | 30.757 | 4.662 | 0.749 | 2.749 | 6596.69 | 30.7 | 2.7 | 6596.7
PANNEAU | +0.000 | 4459.8 | 35.352 | 4.611 | 0.87 | 3.194 | 7666.54 | 35.4 | 3.2 | 7666.5
PANNEAU | +0.000 | 3840.2 | 30.46 | 4.665 | 0.741 | 2.72 | 6528.8 | 30.5 | 2.7 | 6528.8
PANNEAU | +0.000 | 3879.7 | 30.766 | 4.663 | 0.749 | 2.749 | 6598.59 | 30.7 | 2.7 | 6598.6
PANNEAU | +0.000 | 4401.7 | 35.02 | 4.604 | 0.864 | 3.169 | 7606.39 | 35 | 3.2 | 7606.4
PANNEAU | +0.000 | 1222.8 | 10.734 | 5.108 | 0.239 | 0.876 | 2101.53 | 10.7 | 0.9 | 2101.5
PANNEAU | +0.000 | 1245 | 10.874 | 5.104 | 0.242 | 0.888 | 2130.34 | 10.9 | 0.9 | 2130.3
PANNEAU | +0.000 | 891.7 | 7.663 | 5.771 | 0.151 | 0.553 | 1327.81 | 7.7 | 0.6 | 1327.8
PANNEAU | +0.000 | 1230.4 | 10.412 | 5.306 | 0.223 | 0.818 | 1962.19 | 10.4 | 0.9 | 1962.2
PANNEAU | +0.000 | 5370.6 | 42.463 | 4.586 | 1.051 | 3.858 | 9259.35 | 42.5 | 3.9 | 9259.3
PANNEAU | +0.000 | 3864.3 | 30.65 | 4.663 | 0.746 | 2.739 | 6572.74 | 30.6 | 2.7 | 6572.7
PANNEAU | +0.000 | 3858.4 | 30.603 | 4.663 | 0.745 | 2.734 | 6561.88 | 30.6 | 2.7 | 6561.9
PANNEAU | +0.000 | 4460.8 | 35.361 | 4.611 | 0.871 | 3.195 | 7668.69 | 35.4 | 3.2 | 7668.7
PANNEAU | +0.000 | 3866.6 | 30.667 | 4.663 | 0.747 | 2.74 | 6576.69 | 30.7 | 2.7 | 6576.7
PANNEAU | -0.000 | 3863.9 | 30.646 | 4.663 | 0.746 | 2.739 | 6571.73 | 30.6 | 2.7 | 6571.7
PANNEAU | -0.000 | 4455.9 | 26.891 | 5.01 | 0.87 | 2.236 | 5367.52 | 26.9 | 2.2 | 5367.5
PANNEAU | -0.000 | 3848 | 30.521 | 4.665 | 0.743 | 2.726 | 6542.79 | 30.5 | 2.7 | 6542.8
PANNEAU | -0.000 | 5366.4 | 42.533 | 4.585 | 1.053 | 3.865 | 9276.51 | 42.5 | 3.9 | 9276.5
PANNEAU | -0.000 | 6496.8 | 50.962 | 4.562 | 1.268 | 4.655 | 11171.7 | 51 | 4.7 | 11171.7
PANNEAU | -0.000 | 3940.8 | 31.331 | 4.641 | 0.766 | 2.813 | 6750.38 | 31.3 | 2.8 | 6750.4
PANNEAU | -0.000 | 4461.4 | 35.364 | 4.611 | 0.871 | 3.195 | 7669.19 | 35.4 | 3.2 | 7669.2

# IfcWall: 3760*200, PANNEAU
In: Undefined
Description: 3760*200; Material: CONCRETE/C25/30
Tekla Commun - Nom: PANNEAU; Profil: 3760*200; Matériau: C25/30; Classe: 2; Phase: 1; Repère: Béton_PA-10(?); Repère assemblage: PA0(?); Niveau haut: +3.760; Niveau bas: +0.000
Tekla Quantités - Longueur: 10290.2 mm; Largeur: 200 mm; Hauteur: 3760 mm; Surface nette: 82.521 m2; Surface par tonne: 4.487 m2; Surface: 2.038 m2; Volume: 7.663 m3; Poids: 18391.1 kg
WallBaseQuantities - Longueur: 10290.2 mm; Surface extérieure: 82.5 m2; Volume net: 7.7 m3; Poids net: 18391.1 kg

# IfcWallStandardCase: 2820*150, PANNEAU
In: Undefined
Description: 2820*150; Material: CONCRETE/C25/30

# IfcWallStandardCase: 3420*145, MOB 145x45
In: Undefined
Description: 3420*145; Material: TIMBER/C24

# IfcWallStandardCase: 3630*200 (2)
In: Undefined
Description: 3630*200; Material: CONCRETE/C25/30

# IfcWallStandardCase: 3670*200, PANNEAU
In: Undefined
Description: 3670*200; Material: CONCRETE/C25/30

# IfcWallStandardCase: 3760*200 (2)
In: Undefined
Description: 3760*200; Material: CONCRETE/C25/30

# IfcWallStandardCase: 5000*200 (7)
In: Undefined
Description: 5000*200; Material: CONCRETE/C25/30
